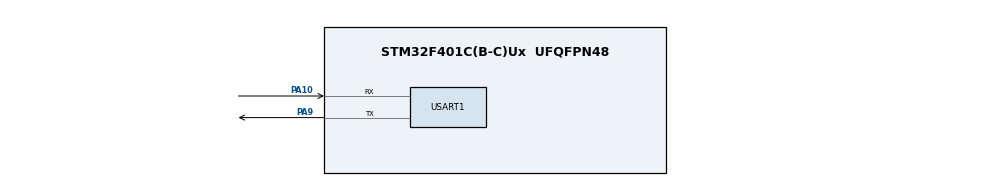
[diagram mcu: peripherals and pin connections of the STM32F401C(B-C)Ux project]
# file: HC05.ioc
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Mcu.Family=STM32F4
Mcu.Name=STM32F401C(B-C)Ux
Mcu.Package=UFQFPN48
NVIC.PriorityGroup=NVIC_PRIORITYGROUP_4
NVIC.USART1_IRQn=true\:0\:0\:false\:false\:true\:true\:true\:true
PA10.Mode=Asynchronous
PA10.Signal=USART1_RX
PA9.Mode=Asynchronous
PA9.Signal=USART1_TX
PH0\ -\ OSC_IN.Mode=HSE-External-Oscillator
PH0\ -\ OSC_IN.Signal=RCC_OSC_IN
PH1\ -\ OSC_OUT.Mode=HSE-External-Oscillator
PH1\ -\ OSC_OUT.Signal=RCC_OSC_OUT
ProjectManager.HeapSize=0x200
ProjectManager.StackSize=0x400
ProjectManager.TargetToolchain=STM32CubeIDE
RCC.48MHZClocksFreq_Value=42000000
RCC.AHBFreq_Value=84000000
RCC.APB1CLKDivider=RCC_HCLK_DIV2
RCC.APB1Freq_Value=42000000
RCC.APB1TimFreq_Value=84000000
RCC.APB2Freq_Value=84000000
RCC.APB2TimFreq_Value=84000000
RCC.CortexFreq_Value=84000000
RCC.HCLKFreq_Value=84000000
RCC.HSE_VALUE=25000000
RCC.HSI_VALUE=16000000
RCC.LSE_VALUE=32768
RCC.PLLM=8
RCC.PLLN=84
RCC.SYSCLKFreq_VALUE=84000000
RCC.SYSCLKSource=RCC_SYSCLKSOURCE_PLLCLK
RCC.VCOOutputFreq_Value=168000000
USART1.VirtualMode=VM_ASYNC
board=custom

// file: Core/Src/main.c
#include "main.h"

UART_HandleTypeDef huart1; // Use UART_HandleTypeDef here
uint8_t rxData;

void SystemClock_Config(void);
static void MX_GPIO_Init(void);
static void MX_USART1_UART_Init(void);

int main(void)
{
	HAL_Init();
	  SystemClock_Config();

	  MX_GPIO_Init();
	  MX_USART1_UART_Init();
	  HAL_UART_Receive_IT(&huart1, &rxData, 1); // Use huart1 for UART functions

  while (1)
  {

  }
}

void SystemClock_Config(void)
{
  RCC_OscInitTypeDef RCC_OscInitStruct = {0};
  RCC_ClkInitTypeDef RCC_ClkInitStruct = {0};

  /** Initializes the RCC Oscillators according to the specified parameters
  * in the RCC_OscInitTypeDef structure.
  */
  RCC_OscInitStruct.OscillatorType = RCC_OSCILLATORTYPE_HSE;
  RCC_OscInitStruct.HSEState = RCC_HSE_ON;
  RCC_OscInitStruct.HSIState = RCC_HSI_ON;
  RCC_OscInitStruct.PLL.PLLState = RCC_PLL_ON;
  RCC_OscInitStruct.PLL.PLLSource = RCC_PLLSOURCE_HSE;
  RCC_OscInitStruct.PLL.PLLM = 4;
  RCC_OscInitStruct.PLL.PLLN = 180;
  RCC_OscInitStruct.PLL.PLLP = RCC_PLLP_DIV2;
  RCC_OscInitStruct.PLL.PLLQ = 4;
  if (HAL_RCC_OscConfig(&RCC_OscInitStruct) != HAL_OK)
  {
    Error_Handler();
  }
  /** Initializes the CPU, AHB and APB buses clocks
  */
  RCC_ClkInitStruct.ClockType = RCC_CLOCKTYPE_HCLK|RCC_CLOCKTYPE_SYSCLK
                              |RCC_CLOCKTYPE_PCLK1|RCC_CLOCKTYPE_PCLK2;
  RCC_ClkInitStruct.SYSCLKSource = RCC_SYSCLKSOURCE_PLLCLK;
  RCC_ClkInitStruct.AHBCLKDivider = RCC_SYSCLK_DIV1;
  RCC_ClkInitStruct.APB1CLKDivider = RCC_HCLK_DIV4;
  RCC_ClkInitStruct.APB2CLKDivider = RCC_HCLK_DIV2;

  if (HAL_RCC_ClockConfig(&RCC_ClkInitStruct, FLASH_LATENCY_5) != HAL_OK)
  {
    Error_Handler();
  }
}

static void MX_USART1_UART_Init(void)
{

  huart1.Instance = USART1;
  huart1.Init.BaudRate = 9600;
  huart1.Init.WordLength = UART_WORDLENGTH_8B;
  huart1.Init.StopBits = UART_STOPBITS_1;
  huart1.Init.Parity = UART_PARITY_NONE;
  huart1.Init.Mode = UART_MODE_TX_RX;
  huart1.Init.HwFlowCtl = UART_HWCONTROL_NONE;
  huart1.Init.OverSampling = UART_OVERSAMPLING_16;
  if (HAL_UART_Init(&huart1) != HAL_OK)
  {
    Error_Handler();
  }
}

static void MX_GPIO_Init(void)
{
  GPIO_InitTypeDef GPIO_InitStruct = {0};

  /* GPIO Ports Clock Enable */
  __HAL_RCC_GPIOD_CLK_ENABLE();
  __HAL_RCC_GPIOA_CLK_ENABLE();

  /*Configure GPIO pin Output Level */
  HAL_GPIO_WritePin(GPIOA, GPIO_PIN_3, GPIO_PIN_RESET);

  /*Configure GPIO pin : PA3 */
  GPIO_InitStruct.Pin = GPIO_PIN_3;
  GPIO_InitStruct.Mode = GPIO_MODE_OUTPUT_PP;
  GPIO_InitStruct.Pull = GPIO_NOPULL;
  GPIO_InitStruct.Speed = GPIO_SPEED_FREQ_LOW;
  HAL_GPIO_Init(GPIOA, &GPIO_InitStruct);
}

/* USER CODE BEGIN 4 */

void HAL_UART_RxCpltCallback(UART_HandleTypeDef *huart) // Use UART_HandleTypeDef here
{
  if (huart->Instance == USART1)
  {
    printf("Received: %c\n", rxData);  // Print the received character
    if (rxData == 79) // ASCII value of 'O' is 79
    {
      HAL_GPIO_WritePin(GPIOA, GPIO_PIN_3, 1);
    }
    else if (rxData == 88) // ASCII value of 'X' is 88
    {
      HAL_GPIO_WritePin(GPIOA, GPIO_PIN_3, 0);
    }
    HAL_UART_Receive_IT(&huart1, &rxData, 1); // Enabling interrupt receive again
  }
}

int __io_putchar(int ch)
{
    HAL_UART_Transmit(&huart1, (uint8_t *)&ch, 1, HAL_MAX_DELAY); // Use HAL_UART_Transmit here
    return ch;
}
/* USER CODE END 4 */

void Error_Handler(void)
{
  __disable_irq();
  while (1)
  {
  }
}
